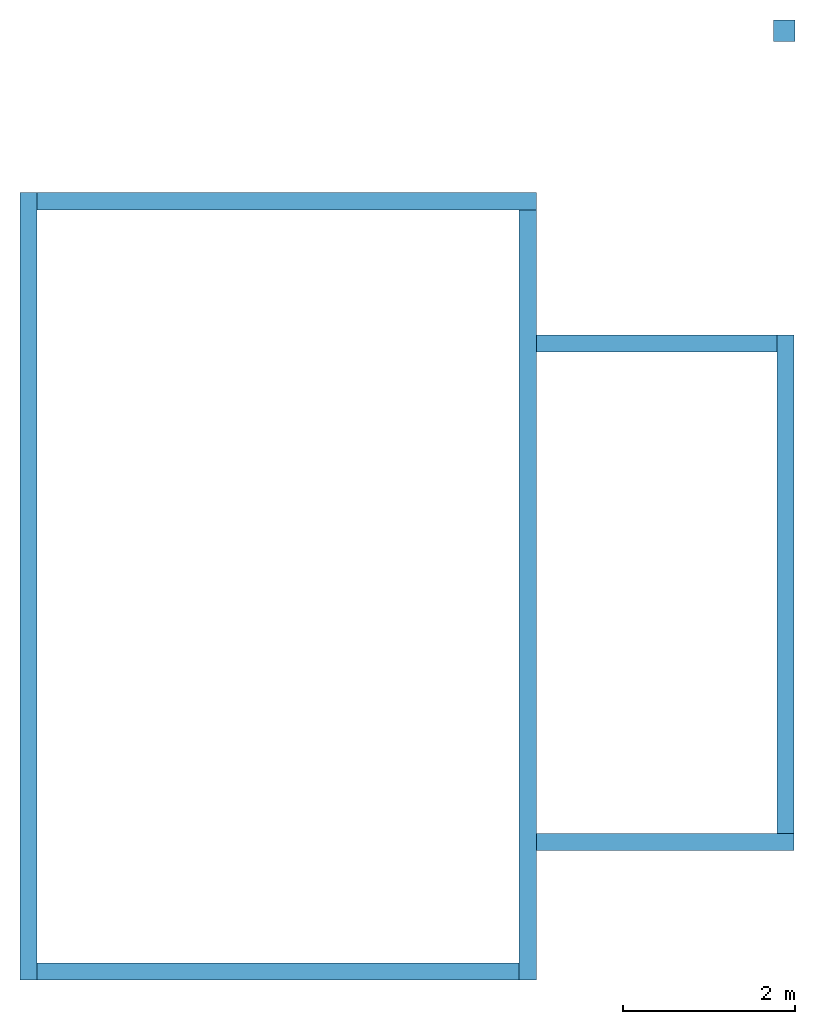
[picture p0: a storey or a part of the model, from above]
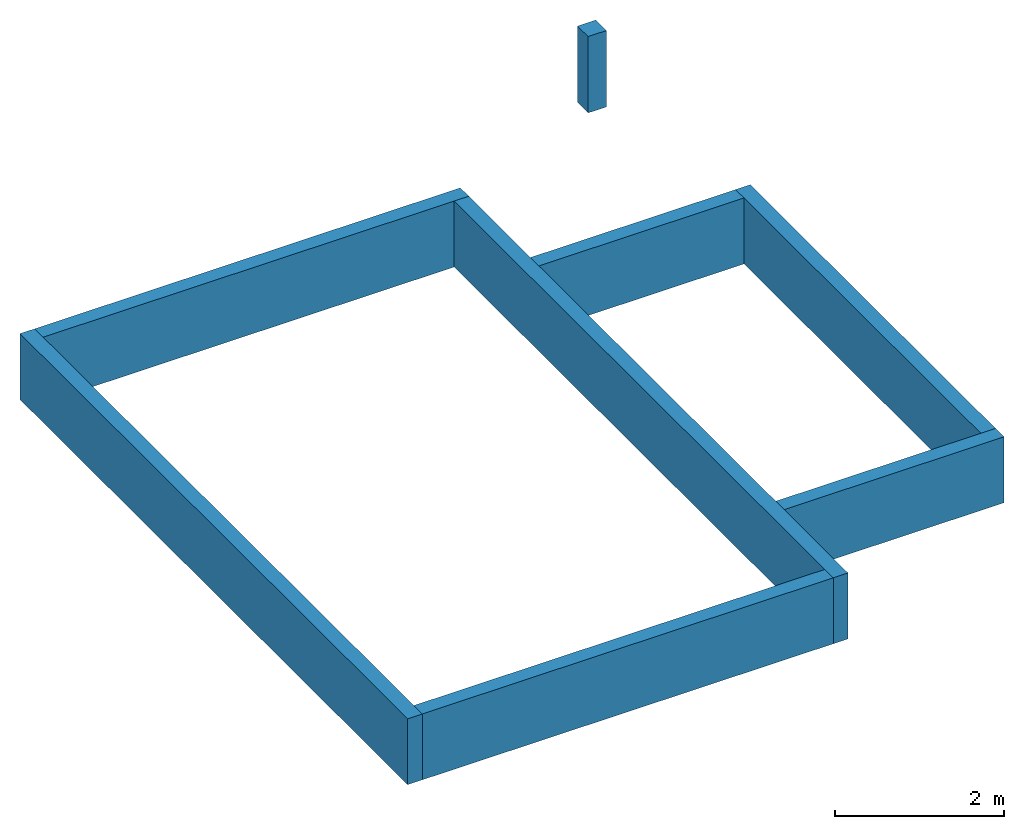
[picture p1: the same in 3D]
Properties of the parts of a building model (IFC2X3)

# File
Description: ViewDefinition [CoordinationView]
File name: Numéro du projet
Time: 2015-04-22T06:04:37
Written by: The EXPRESS Data Manager Version 5.02.0100.07 : 28 Aug 2013
Made in: 20140223_1515(x64) - Exporter 2015.0.2014.0223 - Default UI
Comment: STEP Physical File produced by: The EXPRESS Data Manager Version 5.02.0100.07 : 28 Aug 2013 * Module: EDMstepFileFactory/EDMstandAlone * Creation date: Wed Apr 22 06:04:37 2015 * Host: vincent-HP * Database: C:\Users\vincent\AppData\Local\Temp\{366B2BCF-51C6-43BE-8C63-EB5E309D9138}\ifc * Database version: 5507 * Database creation date: Wed Apr 22 06:04:33 2015 * Schema: IFC2X3 * Model: DataRepository.ifc * Model creation date: Wed Apr 22 06:04:33 2015 * Header model: DataRepository.ifc_HeaderModel * Header model creation date: Wed Apr 22 06:04:33 2015 * EDMuser: sdai-user * EDMgroup: sdai-group * License ID and type: 5605 : Permanent license. Expiry date: * EDMstepFileFactory options: 020000

# IfcProject, Numéro du projet
LongName: Nom du projet; Phase: Etat du projet

# IfcSite, Surface:259560
RefLatitude: 48, 51, 23, 999633; RefLongitude: 2, 21, 3, 553905; RefElevation: 0 m
Autre - Catégorie: Topographie; Déblais: 0 m3; Déblais/remblais net: 0 m3; Remblais: 0 m3
Cotes - Surface: 351.245 m2; Surface projetée: 349.356 m2
Phase de construction - Phase de création: Nouvelle construction

# IfcBuilding
Pset_BuildingCommon - NumberOfStoreys: 4
Autre - Adresse du projet: Entrer l'adresse ici; Catégorie: Informations sur le projet; Date de fin du projet: Date de fin; Etat du projet: Etat du projet; Nom du client: Propriétaire; Nom du projet: Nom du projet; Numéro de projet: Numéro du projet

# IfcBuildingStorey (4)
Autre - Catégorie: Niveaux; Famille: Niveau: Ligne du Niveau; Famille et type: Niveau: Ligne du Niveau; ID du type: Niveau: Ligne du Niveau; Type: Niveau: Ligne du Niveau; Nom de la famille: Niveau
Cotes - Hauteur de calcul: 0 m
Données d'identification - Structure: no; Etage de bâtiment: yes; Nom du type: Ligne du Niveau
Contraintes - Base de l'élévation: Point de base du projet
Graphismes - Couleur: 12632256; Epaisseur des lignes: 1; Motif des lignes: Tiret point; Symbole: Marqueur de niveau - Point triangulaire: Marqueur de niveau - Point triangulaire; Valeur par défaut du symbole à l'extrémité 1: no; Valeur par défaut du symbole à l'extrémité 2: yes
Name | LongName = Nom | Elevation (m) | Elévation (m)
soubassement | soubassement | -1.1 | -1.1
Niveau 0 | Niveau 0 | -1.94916e-14 | 0
Niveau 1 | Niveau 1 | 2.64 | 2.64
Niveau 2 | Niveau 2 | 5.04 | 5.04

# IfcColumn: 250 x 250, Poteau précoulé - Carré:250 x 250:258963
In: soubassement
Type - ElementType: 250 x 250; PredefinedType: COLUMN; Material: Béton - Béton précoulé - 35 MPa
Type - Autre - Catégorie: Poteaux porteurs; ChanfreinTrans: 0.002 m; Nom de la famille: Poteau précoulé - Carré
Type - Cotes - b: 0.25 m; Chanfrein: 0 m
Type - Données d'identification - Nom du type: 250 x 250
Type - Structure - Forme de coupe: 0
Pset_ColumnCommon - IsExternal: no; LoadBearing: yes; Reference: 250 x 250; Slope: 0 deg
Autre - Famille: Poteau précoulé - Carré: 250 x 250; Famille et type: Poteau précoulé - Carré: 250 x 250; ID du type: Poteau précoulé - Carré: 250 x 250; P. de l'armature simple: 0.49 kN; P. des quadrillages d'armature: 0.98 kN; P. du tirant: 0.294 kN; Type: Poteau précoulé - Carré: 250 x 250
Contraintes - Décalage inférieur: 0 m; Décalage supérieur: 0 m; Limite de pièce: yes; Niveau: Niveau: soubassement; Niveau de base: Niveau: soubassement; Niveau supérieur: Niveau: Niveau 0; Se déplace avec les quadrillages: yes; Style de poteau: Vertical
Cotes - Longueur: 1.1 m; Surface: 0.6125 m2; Volume: 0.06875 m3
Matériaux et finitions - Matériau structurel: Béton - Béton précoulé - 35 MPa
Phase de construction - Phase de création: Nouvelle construction
Structure - Activer le modèle analytique: yes; Enrobage d'armature - Autres faces: Paramètres de l'enrobage d'armature: Enrobage d'armature 1; Enrobage d'armature - Face inférieure: Paramètres de l'enrobage d'armature: Enrobage d'armature 1; Enrobage d'armature - Face supérieure: Paramètres de l'enrobage d'armature: Enrobage d'armature 1; Poids de l'armature simple: 50; Poids des quadrillages d'armature: 100; Poids du tirant: 30

# IfcDoor: 0.83m x 2.15m, Entrée - 01:0.83m x 2.15m:256776
In: Niveau 0
Type - OperationType: SINGLE_SWING_LEFT; ParameterTakesPrecedence: no; Sizeable: no; Material: Porte d'entrée - Poignée, Porte d'entrée - Cadre, Verre, Porte d'entrée - Panneau
Type - Entrée - 01:0.83m x 2.15m:256776 - PanelOperation: SWINGING
Type - Autre - Catégorie: Portes; Nom de la famille: Entrée - 01
Type - Construction - Fonction: Extérieur; Fermeture du mur: Par hôte
Type - Contraintes - Sys: 0 m; Déc. Vitre (Auto): 0.02 m; Haut. Deco (Auto): 0.265 m; Tiers Hauteur (Auto): 0.716667 m
Type - Cotes - Epaisseur: 0.05 m; Hauteur: 2.15 m; Hauteur de la poignée: 1 m; Larg. Feuillure: 0.05 m; Largeur: 0.83 m; Prof. Feuillure: 0.07 m
Type - Données d'identification - Marque de type: 31; Nom du type: 0.83m x 2.15m
Type - Matériaux et finitions - Dormants: Porte d'entrée - Cadre; Panneau: Porte d'entrée - Panneau; Poignée: Porte d'entrée - Poignée
Type - Propriétés analytiques - Coefficient d'apport thermique solaire: 0; Transmission de la lumière visible: 0; Coefficient de transfert de chaleur (U): 3.7021; Construction analytique: Métal; Résistance thermique (R): 0.270117
OverallHeight: 2.21 m; OverallWidth: 0.95 m
Pset_DoorCommon - IsExternal: yes; Reference: 0.83m x 2.15m; ThermalTransmittance: 3.7021 kg/K/s3
Autre - ID hôte: Mur de base: Ext. Parpaing 20; Famille: Entrée - 01: 0.83m x 2.15m; Famille et type: Entrée - 01: 0.83m x 2.15m; Hauteur sous linteau: 2.15 m; ID du type: Entrée - 01: 0.83m x 2.15m; Type: Entrée - 01: 0.83m x 2.15m
Contraintes - Hauteur de l'appui: 0 m; Niveau: Niveau: Niveau 0
Cotes - Surface: 2.6733 m2; Volume: 0.114425 m3
Données d'identification - Identifiant: 5
Phase de construction - Phase de création: Nouvelle construction

# IfcDoor: 0.93m x 2.15m, Entrée - 01:0.93m x 2.15m:238684
In: Niveau 0
Type - OperationType: SINGLE_SWING_RIGHT; ParameterTakesPrecedence: no; Sizeable: no; Material: Porte d'entrée - Poignée, Porte d'entrée - Cadre, Verre, Porte d'entrée - Panneau
Type - Entrée - 01:0.93m x 2.15m:238684 - PanelOperation: SWINGING
Type - Autre - Catégorie: Portes; Nom de la famille: Entrée - 01
Type - Construction - Fonction: Extérieur; Fermeture du mur: Par hôte
Type - Contraintes - Déc. Vitre (Auto): 0.02 m; Haut. Deco (Auto): 0.315 m; Sys: 0 m; Tiers Hauteur (Auto): 0.716667 m
Type - Cotes - Epaisseur: 0.05 m; Hauteur: 2.15 m; Hauteur de la poignée: 1 m; Larg. Feuillure: 0.05 m; Largeur: 0.93 m; Prof. Feuillure: 0.07 m
Type - Données d'identification - Marque de type: 29; Nom du type: 0.93m x 2.15m
Type - Matériaux et finitions - Dormants: Porte d'entrée - Cadre; Panneau: Porte d'entrée - Panneau; Poignée: Porte d'entrée - Poignée
Type - Propriétés analytiques - Coefficient d'apport thermique solaire: 0; Coefficient de transfert de chaleur (U): 3.7021; Construction analytique: Métal; Résistance thermique (R): 0.270117; Transmission de la lumière visible: 0
OverallHeight: 2.21 m; OverallWidth: 1.05 m
Pset_DoorCommon - IsExternal: yes; Reference: 0.93m x 2.15m; ThermalTransmittance: 3.7021 kg/K/s3
Autre - Famille: Entrée - 01: 0.93m x 2.15m; Famille et type: Entrée - 01: 0.93m x 2.15m; Hauteur sous linteau: 2.15 m; ID du type: Entrée - 01: 0.93m x 2.15m; ID hôte: Mur de base: Ext. Parpaing 20 + Isolant 8; Type: Entrée - 01: 0.93m x 2.15m
Contraintes - Hauteur de l'appui: 0 m; Niveau: Niveau: Niveau 0
Cotes - Surface: 2.9073 m2; Volume: 0.125655 m3
Données d'identification - Identifiant: 1
Phase de construction - Phase de création: Nouvelle construction

# IfcDoor: 2.4m x 2m, Garage basculante:2.4m x 2m:256467
In: Niveau 0
Type - OperationType: ROLLINGUP; ParameterTakesPrecedence: no; Sizeable: no; Material: Plastique - Noir, Peinture - Grise
Type - Garage basculante:2.4m x 2m:256467 - PanelOperation: ROLLINGUP
Type - Autre - Catégorie: Portes; Nom de la famille: Garage basculante
Type - Construction - Fonction: Extérieur; Fermeture du mur: Par hôte
Type - Cotes - Hauteur: 2 m; Hauteur de la poignée: 0.5 m; Largeur: 2.4 m; Largeur du cadre: 0.06 m
Type - Données d'identification - Marque de type: 30; Nom du type: 2.4m x 2m
Type - Matériaux et finitions - Cadre: Peinture - Grise; Panneau: Peinture - Grise; Poignée: Plastique - Noir
Type - Propriétés analytiques - Coefficient d'apport thermique solaire: 0; Transmission de la lumière visible: 0; Coefficient de transfert de chaleur (U): 3.7021; Construction analytique: Métal; Résistance thermique (R): 0.270117
OverallHeight: 2.43 m; OverallWidth: 2.015 m
Pset_DoorCommon - IsExternal: yes; Reference: 2.4m x 2m; ThermalTransmittance: 3.7021 kg/K/s3
Autre - ID hôte: Mur de base: Ext. Parpaing 20; Famille: Garage basculante: 2.4m x 2m; Famille et type: Garage basculante: 2.4m x 2m; Hauteur sous linteau: 2 m; ID du type: Garage basculante: 2.4m x 2m; Type: Garage basculante: 2.4m x 2m
Contraintes - Hauteur de l'appui: 0 m; Niveau: Niveau: Niveau 0
Cotes - Surface: 5.6962 m2; Volume: 0.21156 m3
Données d'identification - Identifiant: 3
Phase de construction - Phase de création: Nouvelle construction

# IfcRailing: Garde-corps:Type Bateau, Garde-corps:Type Bateau:259283
In: Niveau 0
Material: Peinture - Grise, Pin (1)
Pset_RailingCommon - IsExternal: no; Reference: Type Bateau; Height: 0.9 m
Autre - Catégorie: Garde-corps; Famille: Garde-corps: Type Bateau; Famille et type: Garde-corps: Type Bateau; ID du type: Garde-corps: Type Bateau; Type: Garde-corps: Type Bateau; Nom de la famille: Garde-corps
Contraintes - Décalage inférieur: 0 m; Décalage marche/limon à la française: 0 m; Niveau de base: Niveau: Niveau 0
Cotes - Longueur: 14.65 m
Phase de construction - Phase de création: Nouvelle construction
Construction - Connexion des traverses: Ajuster; Décalage des barreaux: 0 m; Hauteur du garde-corps: 0.9 m; Joints d'angle: Ajouter des segments verticaux/horizontaux; Joints tangents: Prolonger la traverse jusqu'à; Réglage de la hauteur du palier: 0 m; Utiliser le réglage de la hauteur du palier: Non
Données d'identification - Nom du type: Type Bateau
Main courante 1 - Position: Aucune; sets with these values: 2
Traverse haute - Hauteur: 0.9 m; Type: Type de traverse haute: Elliptique - Bois

# IfcRoof: Toit de base:Toit - 200 mm (3)
Pset_RoofCommon - IsExternal: yes; Reference: Toit - 200 mm
Autre - Catégorie: Toits; Famille: Toit de base: Toit - 200 mm; Famille et type: Toit de base: Toit - 200 mm; ID du type: Toit de base: Toit - 200 mm; Type: Toit de base: Toit - 200 mm; Nom de la famille: Toit de base
Construction - Chevron ou ferme: Ferme; Coupe en chevron: Coupe verticale; Profondeur du bord de toiture: 0 m; Epaisseur par défaut: 0.2 m
Contraintes - Lié au volume: no; Limite de pièce: yes; Décalage de la coupure: 0 m; Décalage inférieur à partir du niveau: 0 m
Cotes - Epaisseur: 0.2 m; Inclinaison: 0.286745
Phase de construction - Phase de création: Nouvelle construction
Données d'identification - Nom du type: Toit - 200 mm
Graphismes - Couleur vue détail faible: 0
Propriétés analytiques - Rugosité: 3; Coefficient d'absorbance: 0.7
Name (Toit de base:Toit - 200 mm:...) | In | TotalArea (m2) = Surface (m2) | ProjectedArea (m2) | Hauteur maximale de l'arrête (m) | Niveau de base | Volume (m3)
254509 | Niveau 1 | 6.86598 | 6.6 | 3.10613 | Niveau: Niveau 1 | 1.3732
254849 | Niveau 2 | 53.9915 | 51.9 | 6.43088 | Niveau: Niveau 2 | 10.7983
254919 | Niveau 1 | 19.9737 | 19.2 | 3.7083 | Niveau: Niveau 1 | 3.99475

# IfcSlab: Sol:Dalle en béton - 150 mm (4)
PredefinedType: FLOOR; Material: Maçonnerie - Béton 0.15 m
Pset_SlabCommon - Reference: Dalle en béton - 150 mm; IsExternal: no; LoadBearing: yes; PitchAngle: 0 deg
Autre - Catégorie: Sols; Famille: Sol: Dalle en béton - 150 mm; Famille et type: Sol: Dalle en béton - 150 mm; ID du type: Sol: Dalle en béton - 150 mm; Type: Sol: Dalle en béton - 150 mm; Nom de la famille: Sol
Contraintes - Lié au volume: no; Limite de pièce: yes; Décalage par rapport au niveau: 0 m
Cotes - Epaisseur: 0.15 m
Phase de construction - Phase de création: Nouvelle construction
Construction - Epaisseur par défaut: 0.15 m; Fonction: Intérieur
Données d'identification - Nom du type: Dalle en béton - 150 mm
Graphismes - Couleur vue détail faible: 0
Matériaux et finitions - Matériau structurel: Maçonnerie - Béton
Propriétés analytiques - Rugosité: 3; Coefficient d'absorbance: 0.7
Name (Sol:Dalle en béton - 150 mm:...) | In | Niveau | Périmètre (m) | Surface (m2) | Volume (m3) | Activer le modèle analytique = Structure
247882 | Niveau 0 | Niveau: Niveau 0 | 30.22 | 54.5974 | 8.18961 | no
248055 | Niveau 0 | Niveau: Niveau 0 | 17.96 | 17.94 | 2.691 | no
248748 | Niveau 1 | Niveau: Niveau 1 | 28.62 | 48.7134 | 7.30701 | yes | Structure - Enrobage d'armature - Autres faces: Paramètres de l'enrobage d'armature: Enrobage d'armature 1; Enrobage d'armature - Face inférieure: Paramètres de l'enrobage d'armature: Enrobage d'armature 1; Enrobage d'armature - Face supérieure: Paramètres de l'enrobage d'armature: Enrobage d'armature 1
259838 | Niveau 0 | Niveau: Niveau 0 | 24.4 | 37.2 | 5.58 | no

# IfcSlab: Sol:plancher bois, Sol:plancher bois:257363
In: Niveau 0
PredefinedType: FLOOR; Material: Pin 0.05 m
Pset_SlabCommon - IsExternal: no; LoadBearing: yes; PitchAngle: 0 deg; Reference: plancher bois; ThermalTransmittance: 2.4 kg/K/s3
Autre - Catégorie: Sols; Famille: Sol: plancher bois; Famille et type: Sol: plancher bois; ID du type: Sol: plancher bois; Type: Sol: plancher bois; Nom de la famille: Sol
Contraintes - Lié au volume: no; Limite de pièce: yes; Décalage par rapport au niveau: 0 m; Niveau: Niveau: Niveau 0
Cotes - Epaisseur: 0.05 m; Périmètre: 25.3 m; Surface: 23.01 m2; Volume: 1.1505 m3
Phase de construction - Phase de création: Nouvelle construction
Structure - Activer le modèle analytique: no; Structure: no
Construction - Fonction: Intérieur; Epaisseur par défaut: 0.05 m
Données d'identification - Nom du type: plancher bois
Graphismes - Couleur vue détail faible: 0
Matériaux et finitions - Matériau structurel: Pin
Propriétés analytiques - Rugosité: 3; Coefficient d'absorbance: 0.7; Coefficient de transfert de chaleur (U): 2.4; Masse thermique: 64428; Résistance thermique (R): 0.416667

# IfcSlab: Toit de base:Toit - 200 mm (5)
PredefinedType: ROOF; Material: Toit par défaut 0.2 m
Pset_SlabCommon - IsExternal: yes; LoadBearing: yes; Reference: Toit - 200 mm; PitchAngle: 16 deg
Name (Toit de base:Toit - 200 mm:...) | In
254509 | Niveau 1
2 x 254849 | Niveau 2
2 x 254919 | Niveau 1

# IfcWallStandardCase: Mur de base:Ext. Parpaing 2 sans enduit (7)
In: soubassement
Type - PredefinedType: STANDARD; Material: Eléments de maçonnerie en béton 0.2 m
Type - Autre - Catégorie: Murs; Nom de la famille: Mur de base
Type - Construction - Fonction: Extérieur; Retournement aux extrémités: Aucun(e); Retournement aux insertions: Les deux; Largeur: 0.2 m
Type - Données d'identification - Commentaires du type: Ext. Parpaing 20; Nom du type: Ext. Parpaing 2 sans enduit
Type - Graphismes - Couleur vue détail faible: 0
Type - Matériaux et finitions - Matériau structurel: Eléments de maçonnerie en béton
Type - Propriétés analytiques - Coefficient de transfert de chaleur (U): 6.5; Rugosité: 3; Coefficient d'absorbance: 0.7; Masse thermique: 302400; Résistance thermique (R): 0.153846
Autre - Famille: Mur de base: Ext. Parpaing 2 sans enduit; Famille et type: Mur de base: Ext. Parpaing 2 sans enduit; ID du type: Mur de base: Ext. Parpaing 2 sans enduit; Type: Mur de base: Ext. Parpaing 2 sans enduit
Contraintes - Décalage inférieur: 0 m; Extension inférieure: 0 m; Extension supérieure: 0 m; Lié au volume: no; Limite de pièce: yes; Partie inférieure attachée: no; Contrainte inférieure: Niveau: soubassement; Contrainte supérieure: Niveau: Niveau 0
Phase de construction - Phase de création: Nouvelle construction
Structure - Activer le modèle analytique: no; Structure: no; Utilisation structurelle: Non porteur
Pset_WallCommon - LoadBearing: no; IsExternal: yes; Reference: Ext. Parpaing 2 sans enduit; ThermalTransmittance: 6.5 kg/K/s3
Name (Mur de base:Ext. Parpaing 2 sans enduit:...) | Décalage supérieur (m) | Partie supérieure attachée = ExtendToStructure | Hauteur non contrainte (m) | Ligne de justification | Longueur (m) | Surface (m2) | Volume (m3)
235671 | 0 | yes | 1.1 | Nu porteur: Extérieur | 8.95 | 8.6925 | 1.7385
235765 | 0 | yes | 1.1 | Axe porteur | 5.8 | 5.51 | 1.102
235888 | 0 | yes | 1.1 | Axe porteur | 8.95 | 8.5025 | 1.7005
235966 | 0 | yes | 1.1 | Axe porteur | 5.8 | 5.32 | 1.064
236111 | 0 | yes | 1.1 | Axe porteur | 2.995 | 2.84525 | 0.56905
236253 | -0.15 | no | 0.95 | Axe porteur | 5.79 | 5.5005 | 1.1001
236314 | 0 | yes | 1.1 | Axe porteur | 2.995 | 2.65525 | 0.53105

# IfcWallStandardCase: Mur de base:Ext. Parpaing 20 (3)
In: Niveau 0
Type - PredefinedType: STANDARD; Material: Maçonnerie - Enduit 0.01 m, Eléments de maçonnerie en béton 0.2 m
Type - Autre - Catégorie: Murs; Nom de la famille: Mur de base
Type - Construction - Fonction: Extérieur; Retournement aux extrémités: Aucun(e); Retournement aux insertions: Les deux; Largeur: 0.21 m
Type - Données d'identification - Commentaires du type: Ext. Parpaing 20; Nom du type: Ext. Parpaing 20
Type - Graphismes - Couleur vue détail faible: 0
Type - Matériaux et finitions - Matériau structurel: Eléments de maçonnerie en béton
Type - Propriétés analytiques - Coefficient de transfert de chaleur (U): 6.5; Rugosité: 3; Coefficient d'absorbance: 0.7; Masse thermique: 302400; Résistance thermique (R): 0.153846
Autre - Famille: Mur de base: Ext. Parpaing 20; Famille et type: Mur de base: Ext. Parpaing 20; ID du type: Mur de base: Ext. Parpaing 20; Type: Mur de base: Ext. Parpaing 20
Contraintes - Contrainte inférieure: Niveau: Niveau 0; Contrainte supérieure: Niveau: Niveau 1; Décalage inférieur: 0 m; Décalage supérieur: 0 m; Extension inférieure: 0 m; Extension supérieure: 0 m; Lié au volume: no; Ligne de justification: Nu fini: Extérieur; Limite de pièce: yes; Partie inférieure attachée: no; Hauteur non contrainte: 2.64 m
Phase de construction - Phase de création: Nouvelle construction
Structure - Activer le modèle analytique: no; Structure: no; Utilisation structurelle: Non porteur
Pset_WallCommon - LoadBearing: no; IsExternal: yes; Reference: Ext. Parpaing 20; ThermalTransmittance: 6.5 kg/K/s3
Name (Mur de base:Ext. Parpaing 20:...) | Partie supérieure attachée = ExtendToStructure | Longueur (m) | Surface (m2) | Volume (m3)
234860 | no | 3.04 | 3.02355 | 0.634945
234937 | yes | 5.79 | 17.528 | 3.67748
234973 | no | 3.04 | 5.5296 | 1.14277

# IfcWallStandardCase: Mur de base:Ext. Parpaing 20 + Isolant 8 (8)
Type - PredefinedType: STANDARD; Material: Maçonnerie - Enduit 0.01 m, Eléments de maçonnerie en béton 0.2 m, Maçonnerie - Isolant 0.08 m
Type - Autre - Catégorie: Murs; Nom de la famille: Mur de base
Type - Construction - Fonction: Extérieur; Largeur: 0.29 m; Retournement aux extrémités: Aucun(e); Retournement aux insertions: Les deux
Type - Données d'identification - Commentaires du type: Ext. Parpaing 20 + Isolant 10; Nom du type: Ext. Parpaing 20 + Isolant 8
Type - Graphismes - Couleur vue détail faible: 0
Type - Matériaux et finitions - Matériau structurel: Eléments de maçonnerie en béton
Type - Propriétés analytiques - Coefficient d'absorbance: 0.7; Coefficient de transfert de chaleur (U): 6.5; Masse thermique: 302400; Résistance thermique (R): 0.153846; Rugosité: 3
Autre - Famille: Mur de base: Ext. Parpaing 20 + Isolant 8; Famille et type: Mur de base: Ext. Parpaing 20 + Isolant 8; ID du type: Mur de base: Ext. Parpaing 20 + Isolant 8; Type: Mur de base: Ext. Parpaing 20 + Isolant 8
Contraintes - Décalage inférieur: 0 m; Décalage supérieur: 0 m; Extension inférieure: 0 m; Extension supérieure: 0 m; Lié au volume: no; Ligne de justification: Nu fini: Extérieur; Limite de pièce: yes; Partie inférieure attachée: no
Phase de construction - Phase de création: Nouvelle construction
Structure - Activer le modèle analytique: no; Structure: no; Utilisation structurelle: Non porteur
Pset_WallCommon - Reference: Ext. Parpaing 20 + Isolant 8; LoadBearing: no; IsExternal: yes; ThermalTransmittance: 6.5 kg/K/s3
Name (Mur de base:Ext. Parpaing 20 + Isolant 8:...) | In | Contrainte inférieure | Contrainte supérieure | Hauteur non contrainte (m) | Partie supérieure attachée = ExtendToStructure | Longueur (m) | Surface (m2) | Volume (m3)
234535 | Niveau 0 | Niveau: Niveau 0 | Niveau: Niveau 1 | 2.64 | yes | 9.005 | 24.2721 | 7.03892
234577 | Niveau 0 | Niveau: Niveau 0 | Niveau: Niveau 1 | 2.64 | yes | 5.71 | 11.1492 | 3.25302
234705 | Niveau 0 | Niveau: Niveau 0 | Niveau: Niveau 1 | 2.64 | yes | 8.86 | 23.4945 | 6.8134
234745 | Niveau 0 | Niveau: Niveau 0 | Niveau: Niveau 1 | 2.64 | no | 5.71 | 10.8268 | 3.11602
248462 | Niveau 1 | Niveau: Niveau 1 | Niveau: Niveau 2 | 2.4 | yes | 7.96 | 24.6792 | 7.15695
248520 | Niveau 1 | Niveau: Niveau 1 | Niveau: Niveau 2 | 2.4 | no | 5.71 | 12.274 | 3.5545
248596 | Niveau 1 | Niveau: Niveau 1 | Niveau: Niveau 2 | 2.4 | yes | 7.96 | 22.5411 | 6.53196
248665 | Niveau 1 | Niveau: Niveau 1 | Niveau: Niveau 2 | 2.4 | no | 5.71 | 10.914 | 3.1533

# IfcWindow: 0.40m x 0.75m - Appui Béton (3)
Type - ParameterTakesPrecedence: no; Sizeable: no; Material: Fenêtre - Poignée, Fenêtre - Appui, Fenêtre - Vitrage, Fenêtre - Cadre
Type - Autre - Catégorie: Fenêtres; Nom de la famille: 1 Vantail droit - Volet et petits bois
Type - Construction - Appui Alu: no; Fermeture du mur: Extérieur
Type - Contraintes - A. App.: 90 deg; A: 0.035 m; H. App: 0.08 m
Type - Cotes - Ep. Isolant: 0.1 m; Hauteur: 0.75 m; Hauteur de la poignée: 1.4 m; Largeur: 0.4 m
Type - Données d'identification - Marque de type: 17; Nom du type: 0.40m x 0.75m - Appui Béton
Type - Matériaux et finitions - Appui: Fenêtre - Appui; Barres et contreventement: Fenêtre - Cadre; Encadrement Int: Fenêtre - Cadre; Fenêtre: Fenêtre - Cadre; Poignée: Fenêtre - Poignée; Tapées: Fenêtre - Cadre; Vitrage: Fenêtre - Vitrage; Volets: Volets - Bois
Type - Propriétés analytiques - Construction analytique: <Aucun>
OverallHeight: 1.08 m; OverallWidth: 0.5 m
Pset_WindowCommon - IsExternal: yes; Reference: 0.40m x 0.75m - Appui Béton
Autre - Famille: 1 Vantail droit - Volet et petits bois: 0.40m x 0.75m - Appui Béton; Famille et type: 1 Vantail droit - Volet et petits bois: 0.40m x 0.75m - Appui Béton; Hauteur sous linteau: 1.55 m; ID du type: 1 Vantail droit - Volet et petits bois: 0.40m x 0.75m - Appui Béton; Type: 1 Vantail droit - Volet et petits bois: 0.40m x 0.75m - Appui Béton
Contraintes - Hauteur de l'appui: 0.8 m
Graphismes - Encadrement intérieur: no; Petits bois: no; Petits bois 2x2 / 2x3: no; Barres et contreventement_2: no; Volet bois: no
Phase de construction - Phase de création: Nouvelle construction
Name (1 Vantail droit - Volet et petits bois:0.40m x 0.75m - Appui Béton:...) | In | ID hôte | Niveau | Surface (m2) | Volume (m3) | Identifiant
254075 | Niveau 1 | Mur de base: Ext. Parpaing 20 + Isolant 8 | Niveau: Niveau 1 | 1.37569 | 0.0292799 | 10
254098 | Niveau 1 | Mur de base: Ext. Parpaing 20 + Isolant 8 | Niveau: Niveau 1 | 1.37569 | 0.0292799 | 11
254138 | Niveau 0 | Mur de base: Ext. Parpaing 20 | Niveau: Niveau 0 | 1.30862 | 0.0276539 | 12

# IfcWindow: 1.20m x 2.15m, PF 2 Vantaux droits - Volets et petits bois:1.20m x 2.15m:247837
In: Niveau 0
Type - OperationType: DOUBLE_PANEL_VERTICAL; ParameterTakesPrecedence: no; Sizeable: no; Material: Volets - Bois, Peinture - Noir, Fenêtre - Poignée, Fenêtre - Appui, Fenêtre - Cadre, Fenêtre - Vitrage
Type - Autre - Catégorie: Fenêtres; Nom de la famille: PF 2 Vantaux droits - Volets et petits bois
Type - Construction - Fermeture du mur: Extérieur
Type - Contraintes - DL: 0.6 m
Type - Cotes - Ep. Isolant: 0.1 m; Hauteur: 2.15 m; Hauteur de la poignée: 1.1 m; Largeur: 1.2 m
Type - Données d'identification - Marque de type: 16; Nom du type: 1.20m x 2.15m
Type - Matériaux et finitions - Appui: Fenêtre - Appui; Barres et contreventements: Fenêtre - Cadre; Encadrement Int: Fenêtre - Cadre; Fenêtre: Fenêtre - Cadre; Poignée: Fenêtre - Poignée; Tapées: Fenêtre - Cadre; Vitrage: Fenêtre - Vitrage; Volets: Volets - Bois
Type - Propriétés analytiques - Construction analytique: <Aucun>
OverallHeight: 2.265 m; OverallWidth: 2.46 m
Pset_WindowCommon - IsExternal: yes; Reference: 1.20m x 2.15m
Autre - ID hôte: Mur de base: Ext. Parpaing 20 + Isolant 8; Famille: PF 2 Vantaux droits - Volets et petits bois: 1.20m x 2.15m; Famille et type: PF 2 Vantaux droits - Volets et petits bois: 1.20m x 2.15m; Hauteur sous linteau: 2.185 m; ID du type: PF 2 Vantaux droits - Volets et petits bois: 1.20m x 2.15m; Type: PF 2 Vantaux droits - Volets et petits bois: 1.20m x 2.15m
Contraintes - Niveau: Niveau: Niveau 0; Hauteur de l'appui: 0.035 m
Cotes - Surface: 7.21521 m2; Volume: 0.146444 m3
Données d'identification - Identifiant: 3
Graphismes - Barres et contreventements_2: no; Encadrement intérieur: no; Petits bois: no; Volets bois: yes; Petits bois 2x4 / 2x5: no
Phase de construction - Phase de création: Nouvelle construction

# IfcWindow: 1m x 1.35m - Appui Béton (5)
Type - OperationType: DOUBLE_PANEL_VERTICAL; ParameterTakesPrecedence: no; Sizeable: no; Material: Volets - Bois, Peinture - Noir, Fenêtre - Poignée, Fenêtre - Appui, Fenêtre - Cadre, Fenêtre - Vitrage
Type - Autre - Catégorie: Fenêtres; Nom de la famille: 2 Vantaux droits - Volets et petits bois
Type - Construction - Appui Alu: no; Fermeture du mur: Extérieur
Type - Contraintes - A: 0.035 m; A. App.: 90 deg; DL: 0.5 m; H. App: 0.08 m
Type - Cotes - Ep. Isolant: 0.1 m; Hauteur: 1.35 m; Hauteur de la poignée: 1.4 m; Largeur: 1 m
Type - Données d'identification - Marque de type: 15; Nom du type: 1m x 1.35m - Appui Béton
Type - Matériaux et finitions - Appui: Fenêtre - Appui; Barres et contreventements: Fenêtre - Cadre; Encadrement Int: Fenêtre - Cadre; Fenêtre: Fenêtre - Cadre; Poignée: Fenêtre - Poignée; Tapées: Fenêtre - Cadre; Vitrage: Fenêtre - Vitrage; Volets: Volets - Bois
Type - Propriétés analytiques - Construction analytique: <Aucun>
OverallHeight: 1.48 m; OverallWidth: 2.06 m
Pset_WindowCommon - IsExternal: yes; Reference: 1m x 1.35m - Appui Béton
Autre - ID hôte: Mur de base: Ext. Parpaing 20 + Isolant 8; Famille: 2 Vantaux droits - Volets et petits bois: 1m x 1.35m - Appui Béton; Famille et type: 2 Vantaux droits - Volets et petits bois: 1m x 1.35m - Appui Béton; Hauteur sous linteau: 2.15 m; ID du type: 2 Vantaux droits - Volets et petits bois: 1m x 1.35m - Appui Béton; Type: 2 Vantaux droits - Volets et petits bois: 1m x 1.35m - Appui Béton
Contraintes - Hauteur de l'appui: 0.8 m
Cotes - Hauteur de l'appui: 0.8 m; Surface: 4.52375 m2; Volume: 0.0972582 m3
Graphismes - Barres et contreventements_2: no; Encadrement intérieur: no; Petits bois: no; Petits bois 2x2 / 2x3: no; Volets bois: yes
Phase de construction - Phase de création: Nouvelle construction
Name (2 Vantaux droits - Volets et petits bois:1m x 1.35m - Appui Béton:...) | In | Niveau | Identifiant
243233 | Niveau 0 | Niveau: Niveau 0 | 1
243504 | Niveau 0 | Niveau: Niveau 0 | 2
249522 | Niveau 1 | Niveau: Niveau 1 | 7
249575 | Niveau 1 | Niveau: Niveau 1 | 8
249607 | Niveau 1 | Niveau: Niveau 1 | 9
